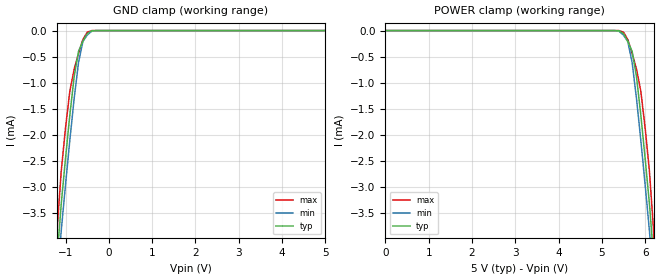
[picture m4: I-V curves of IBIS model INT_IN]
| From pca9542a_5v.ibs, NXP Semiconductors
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[Model]   INT_IN
Model_type Input
Vinh=2.1
Vinl=0.9
C_comp   1.73p   1.73p   1.73p
[Temperature Range] 27   85   -40
[Voltage Range]   5   4.5   5.5
[POWER Clamp Reference]5   4.5   5.5
[GND Clamp Reference]0   0   0
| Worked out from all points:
|   GND clamp passes 1 mA (typ) near -0.82 V on its own axis
[GND Clamp]
-2V       -10.34A    -9.213A    -11.78A
-1.2V     -4.404mA   -4.893mA   -3.887mA
-1.1V     -3.331mA   -3.847mA   -2.702mA
-1V       -2.45mA    -2.956mA   -1.863mA
-900mV    -1.615mA   -2.099mA   -1.157mA
-800mV    -878.5uA   -1.295mA   -736.9uA
-700mV    -398.8uA   -611.9uA   -437.9uA
-600mV    -204.6uA   -211.1uA   -172.5uA
-500mV    -59.3uA    -86.78uA   -30.32uA
-400mV    -5.902uA   -15.55uA   -1.031uA
-300mV    -168.4nA   -810nA     -11nA
5V        16.36pA    33.47pA    15.01pA
[POWER Clamp]
0V        16.36pA    33.47pA    15.01pA
5.3V      -168.4nA   -810nA     -11nA
5.4V      -5.902uA   -15.55uA   -1.031uA
5.5V      -59.3uA    -86.78uA   -30.32uA
5.6V      -204.6uA   -211.1uA   -172.5uA
5.7V      -398.8uA   -612uA     -437.9uA
5.8V      -878.6uA   -1.295mA   -736.9uA
5.9V      -1.615mA   -2.099mA   -1.157mA
6V        -2.45mA    -2.956mA   -1.863mA
6.1V      -3.331mA   -3.847mA   -2.702mA
6.2V      -4.404mA   -4.893mA   -3.887mA
7V        -10.34A    -9.213A    -11.78A
